VERSION 5.4 ;
NAMESCASESENSITIVE ON ;
BUSBITCHARS "[]" ;
DIVIDERCHAR "/" ;
UNITS
  DATABASE MICRONS 2000 ;
END UNITS
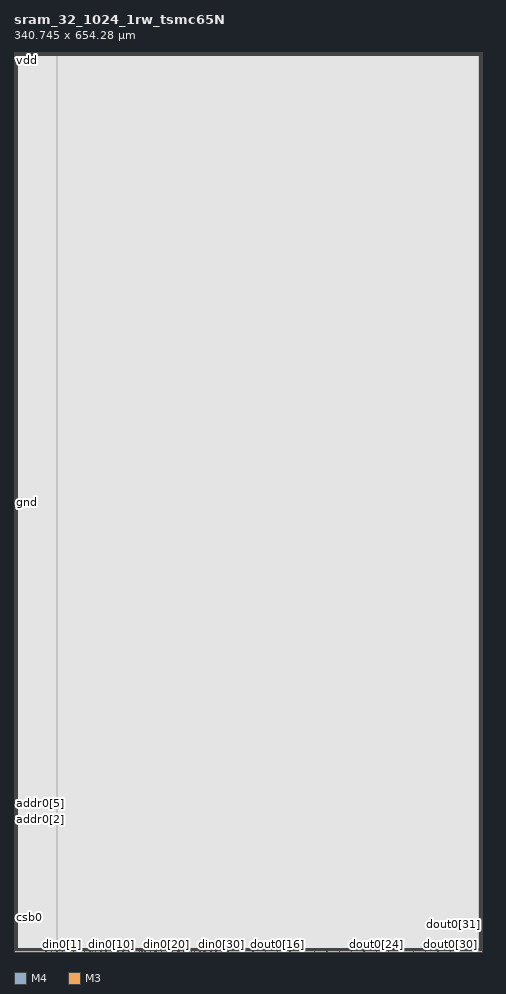
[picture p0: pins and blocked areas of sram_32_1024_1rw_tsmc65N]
MACRO sram_32_1024_1rw_tsmc65N
   CLASS BLOCK ;
   SIZE 340.745 BY 654.28 ;
   SYMMETRY X Y R90 ;
   PIN din0[0]
      DIRECTION INPUT ;
      PORT
         LAYER M4 ;
         RECT  31.095 0.0 31.315 0.22 ;
      END
   END din0[0]
   PIN din0[1]
      DIRECTION INPUT ;
      PORT
         LAYER M4 ;
         RECT  35.095 0.0 35.315 0.22 ;
      END
   END din0[1]
   PIN din0[2]
      DIRECTION INPUT ;
      PORT
         LAYER M4 ;
         RECT  39.095 0.0 39.315 0.22 ;
      END
   END din0[2]
   PIN din0[3]
      DIRECTION INPUT ;
      PORT
         LAYER M4 ;
         RECT  43.095 0.0 43.315 0.22 ;
      END
   END din0[3]
   PIN din0[4]
      DIRECTION INPUT ;
      PORT
         LAYER M4 ;
         RECT  47.095 0.0 47.315 0.22 ;
      END
   END din0[4]
   PIN din0[5]
      DIRECTION INPUT ;
      PORT
         LAYER M4 ;
         RECT  51.095 0.0 51.315 0.22 ;
      END
   END din0[5]
   PIN din0[6]
      DIRECTION INPUT ;
      PORT
         LAYER M4 ;
         RECT  55.095 0.0 55.315 0.22 ;
      END
   END din0[6]
   PIN din0[7]
      DIRECTION INPUT ;
      PORT
         LAYER M4 ;
         RECT  59.095 0.0 59.315 0.22 ;
      END
   END din0[7]
   PIN din0[8]
      DIRECTION INPUT ;
      PORT
         LAYER M4 ;
         RECT  63.095 0.0 63.315 0.22 ;
      END
   END din0[8]
   PIN din0[9]
      DIRECTION INPUT ;
      PORT
         LAYER M4 ;
         RECT  67.095 0.0 67.315 0.22 ;
      END
   END din0[9]
   PIN din0[10]
      DIRECTION INPUT ;
      PORT
         LAYER M4 ;
         RECT  71.095 0.0 71.315 0.22 ;
      END
   END din0[10]
   PIN din0[11]
      DIRECTION INPUT ;
      PORT
         LAYER M4 ;
         RECT  75.095 0.0 75.315 0.22 ;
      END
   END din0[11]
   PIN din0[12]
      DIRECTION INPUT ;
      PORT
         LAYER M4 ;
         RECT  79.095 0.0 79.315 0.22 ;
      END
   END din0[12]
   PIN din0[13]
      DIRECTION INPUT ;
      PORT
         LAYER M4 ;
         RECT  83.095 0.0 83.315 0.22 ;
      END
   END din0[13]
   PIN din0[14]
      DIRECTION INPUT ;
      PORT
         LAYER M4 ;
         RECT  87.095 0.0 87.315 0.22 ;
      END
   END din0[14]
   PIN din0[15]
      DIRECTION INPUT ;
      PORT
         LAYER M4 ;
         RECT  91.095 0.0 91.315 0.22 ;
      END
   END din0[15]
   PIN din0[16]
      DIRECTION INPUT ;
      PORT
         LAYER M4 ;
         RECT  95.095 0.0 95.315 0.22 ;
      END
   END din0[16]
   PIN din0[17]
      DIRECTION INPUT ;
      PORT
         LAYER M4 ;
         RECT  99.095 0.0 99.315 0.22 ;
      END
   END din0[17]
   PIN din0[18]
      DIRECTION INPUT ;
      PORT
         LAYER M4 ;
         RECT  103.095 0.0 103.315 0.22 ;
      END
   END din0[18]
   PIN din0[19]
      DIRECTION INPUT ;
      PORT
         LAYER M4 ;
         RECT  107.095 0.0 107.315 0.22 ;
      END
   END din0[19]
   PIN din0[20]
      DIRECTION INPUT ;
      PORT
         LAYER M4 ;
         RECT  111.095 0.0 111.315 0.22 ;
      END
   END din0[20]
   PIN din0[21]
      DIRECTION INPUT ;
      PORT
         LAYER M4 ;
         RECT  115.095 0.0 115.315 0.22 ;
      END
   END din0[21]
   PIN din0[22]
      DIRECTION INPUT ;
      PORT
         LAYER M4 ;
         RECT  119.095 0.0 119.315 0.22 ;
      END
   END din0[22]
   PIN din0[23]
      DIRECTION INPUT ;
      PORT
         LAYER M4 ;
         RECT  123.095 0.0 123.315 0.22 ;
      END
   END din0[23]
   PIN din0[24]
      DIRECTION INPUT ;
      PORT
         LAYER M4 ;
         RECT  127.095 0.0 127.315 0.22 ;
      END
   END din0[24]
   PIN din0[25]
      DIRECTION INPUT ;
      PORT
         LAYER M4 ;
         RECT  131.095 0.0 131.315 0.22 ;
      END
   END din0[25]
   PIN din0[26]
      DIRECTION INPUT ;
      PORT
         LAYER M4 ;
         RECT  135.095 0.0 135.315 0.22 ;
      END
   END din0[26]
   PIN din0[27]
      DIRECTION INPUT ;
      PORT
         LAYER M4 ;
         RECT  139.095 0.0 139.315 0.22 ;
      END
   END din0[27]
   PIN din0[28]
      DIRECTION INPUT ;
      PORT
         LAYER M4 ;
         RECT  143.095 0.0 143.315 0.22 ;
      END
   END din0[28]
   PIN din0[29]
      DIRECTION INPUT ;
      PORT
         LAYER M4 ;
         RECT  147.095 0.0 147.315 0.22 ;
      END
   END din0[29]
   PIN din0[30]
      DIRECTION INPUT ;
      PORT
         LAYER M4 ;
         RECT  151.095 0.0 151.315 0.22 ;
      END
   END din0[30]
   PIN din0[31]
      DIRECTION INPUT ;
      PORT
         LAYER M4 ;
         RECT  155.095 0.0 155.315 0.22 ;
      END
   END din0[31]
   PIN addr0[0]
      DIRECTION INPUT ;
      PORT
         LAYER M4 ;
         RECT  23.095 0.0 23.315 0.22 ;
      END
   END addr0[0]
   PIN addr0[1]
      DIRECTION INPUT ;
      PORT
         LAYER M4 ;
         RECT  27.095 0.0 27.315 0.22 ;
      END
   END addr0[1]
   PIN addr0[2]
      DIRECTION INPUT ;
      PORT
         LAYER M3 ;
         RECT  0.0 96.12 0.22 96.34 ;
      END
   END addr0[2]
   PIN addr0[3]
      DIRECTION INPUT ;
      PORT
         LAYER M3 ;
         RECT  0.0 98.45 0.22 98.67 ;
      END
   END addr0[3]
   PIN addr0[4]
      DIRECTION INPUT ;
      PORT
         LAYER M3 ;
         RECT  0.0 100.25 0.22 100.47 ;
      END
   END addr0[4]
   PIN addr0[5]
      DIRECTION INPUT ;
      PORT
         LAYER M3 ;
         RECT  0.0 102.05 0.22 102.27 ;
      END
   END addr0[5]
   PIN addr0[6]
      DIRECTION INPUT ;
      PORT
         LAYER M3 ;
         RECT  0.0 103.85 0.22 104.07 ;
      END
   END addr0[6]
   PIN addr0[7]
      DIRECTION INPUT ;
      PORT
         LAYER M3 ;
         RECT  0.0 105.65 0.22 105.87 ;
      END
   END addr0[7]
   PIN addr0[8]
      DIRECTION INPUT ;
      PORT
         LAYER M3 ;
         RECT  0.0 107.45 0.22 107.67 ;
      END
   END addr0[8]
   PIN addr0[9]
      DIRECTION INPUT ;
      PORT
         LAYER M3 ;
         RECT  0.0 109.25 0.22 109.47 ;
      END
   END addr0[9]
   PIN csb0
      DIRECTION INPUT ;
      PORT
         LAYER M3 ;
         RECT  0.0 24.8 0.22 25.02 ;
      END
   END csb0
   PIN web0
      DIRECTION INPUT ;
      PORT
         LAYER M3 ;
         RECT  0.0 26.6 0.22 26.82 ;
      END
   END web0
   PIN clk0
      DIRECTION INPUT ;
      PORT
         LAYER M3 ;
         RECT  0.0 24.45 0.22 24.67 ;
      END
   END clk0
   PIN dout0[0]
      DIRECTION OUTPUT ;
      PORT
         LAYER M4 ;
         RECT  48.25 0.0 48.47 0.22 ;
      END
   END dout0[0]
   PIN dout0[1]
      DIRECTION OUTPUT ;
      PORT
         LAYER M4 ;
         RECT  57.21 0.0 57.43 0.22 ;
      END
   END dout0[1]
   PIN dout0[2]
      DIRECTION OUTPUT ;
      PORT
         LAYER M4 ;
         RECT  66.17 0.0 66.39 0.22 ;
      END
   END dout0[2]
   PIN dout0[3]
      DIRECTION OUTPUT ;
      PORT
         LAYER M4 ;
         RECT  75.48 0.0 75.7 0.22 ;
      END
   END dout0[3]
   PIN dout0[4]
      DIRECTION OUTPUT ;
      PORT
         LAYER M4 ;
         RECT  84.09 0.0 84.31 0.22 ;
      END
   END dout0[4]
   PIN dout0[5]
      DIRECTION OUTPUT ;
      PORT
         LAYER M4 ;
         RECT  93.05 0.0 93.27 0.22 ;
      END
   END dout0[5]
   PIN dout0[6]
      DIRECTION OUTPUT ;
      PORT
         LAYER M4 ;
         RECT  102.01 0.0 102.23 0.22 ;
      END
   END dout0[6]
   PIN dout0[7]
      DIRECTION OUTPUT ;
      PORT
         LAYER M4 ;
         RECT  111.77 0.0 111.99 0.22 ;
      END
   END dout0[7]
   PIN dout0[8]
      DIRECTION OUTPUT ;
      PORT
         LAYER M4 ;
         RECT  119.93 0.0 120.15 0.22 ;
      END
   END dout0[8]
   PIN dout0[9]
      DIRECTION OUTPUT ;
      PORT
         LAYER M4 ;
         RECT  128.89 0.0 129.11 0.22 ;
      END
   END dout0[9]
   PIN dout0[10]
      DIRECTION OUTPUT ;
      PORT
         LAYER M4 ;
         RECT  137.95 0.0 138.17 0.22 ;
      END
   END dout0[10]
   PIN dout0[11]
      DIRECTION OUTPUT ;
      PORT
         LAYER M4 ;
         RECT  146.745 0.0 146.965 0.22 ;
      END
   END dout0[11]
   PIN dout0[12]
      DIRECTION OUTPUT ;
      PORT
         LAYER M4 ;
         RECT  155.77 0.0 155.99 0.22 ;
      END
   END dout0[12]
   PIN dout0[13]
      DIRECTION OUTPUT ;
      PORT
         LAYER M4 ;
         RECT  164.73 0.0 164.95 0.22 ;
      END
   END dout0[13]
   PIN dout0[14]
      DIRECTION OUTPUT ;
      PORT
         LAYER M4 ;
         RECT  173.69 0.0 173.91 0.22 ;
      END
   END dout0[14]
   PIN dout0[15]
      DIRECTION OUTPUT ;
      PORT
         LAYER M4 ;
         RECT  182.65 0.0 182.87 0.22 ;
      END
   END dout0[15]
   PIN dout0[16]
      DIRECTION OUTPUT ;
      PORT
         LAYER M4 ;
         RECT  191.61 0.0 191.83 0.22 ;
      END
   END dout0[16]
   PIN dout0[17]
      DIRECTION OUTPUT ;
      PORT
         LAYER M4 ;
         RECT  200.57 0.0 200.79 0.22 ;
      END
   END dout0[17]
   PIN dout0[18]
      DIRECTION OUTPUT ;
      PORT
         LAYER M4 ;
         RECT  209.53 0.0 209.75 0.22 ;
      END
   END dout0[18]
   PIN dout0[19]
      DIRECTION OUTPUT ;
      PORT
         LAYER M4 ;
         RECT  218.49 0.0 218.71 0.22 ;
      END
   END dout0[19]
   PIN dout0[20]
      DIRECTION OUTPUT ;
      PORT
         LAYER M4 ;
         RECT  227.45 0.0 227.67 0.22 ;
      END
   END dout0[20]
   PIN dout0[21]
      DIRECTION OUTPUT ;
      PORT
         LAYER M4 ;
         RECT  236.41 0.0 236.63 0.22 ;
      END
   END dout0[21]
   PIN dout0[22]
      DIRECTION OUTPUT ;
      PORT
         LAYER M4 ;
         RECT  245.37 0.0 245.59 0.22 ;
      END
   END dout0[22]
   PIN dout0[23]
      DIRECTION OUTPUT ;
      PORT
         LAYER M4 ;
         RECT  254.33 0.0 254.55 0.22 ;
      END
   END dout0[23]
   PIN dout0[24]
      DIRECTION OUTPUT ;
      PORT
         LAYER M4 ;
         RECT  263.29 0.0 263.51 0.22 ;
      END
   END dout0[24]
   PIN dout0[25]
      DIRECTION OUTPUT ;
      PORT
         LAYER M4 ;
         RECT  272.25 0.0 272.47 0.22 ;
      END
   END dout0[25]
   PIN dout0[26]
      DIRECTION OUTPUT ;
      PORT
         LAYER M4 ;
         RECT  281.21 0.0 281.43 0.22 ;
      END
   END dout0[26]
   PIN dout0[27]
      DIRECTION OUTPUT ;
      PORT
         LAYER M4 ;
         RECT  290.17 0.0 290.39 0.22 ;
      END
   END dout0[27]
   PIN dout0[28]
      DIRECTION OUTPUT ;
      PORT
         LAYER M4 ;
         RECT  299.13 0.0 299.35 0.22 ;
      END
   END dout0[28]
   PIN dout0[29]
      DIRECTION OUTPUT ;
      PORT
         LAYER M4 ;
         RECT  308.09 0.0 308.31 0.22 ;
      END
   END dout0[29]
   PIN dout0[30]
      DIRECTION OUTPUT ;
      PORT
         LAYER M4 ;
         RECT  317.05 0.0 317.27 0.22 ;
      END
   END dout0[30]
   PIN dout0[31]
      DIRECTION OUTPUT ;
      PORT
         LAYER M3 ;
         RECT  340.525 20.055 340.745 20.275 ;
      END
   END dout0[31]
   PIN vdd
      DIRECTION INOUT ;
      USE POWER ; 
      SHAPE ABUTMENT ; 
      PORT
         LAYER M4 ;
         RECT  339.845 0.0 340.745 654.28 ;
         LAYER M3 ;
         RECT  0.0 653.38 340.745 654.28 ;
         LAYER M4 ;
         RECT  0.0 0.0 0.9 654.28 ;
         LAYER M3 ;
         RECT  0.0 0.0 340.745 0.9 ;
      END
   END vdd
   PIN gnd
      DIRECTION INOUT ;
      USE GROUND ; 
      SHAPE ABUTMENT ; 
      PORT
         LAYER M4 ;
         RECT  338.045 1.8 338.945 652.48 ;
         LAYER M3 ;
         RECT  1.8 1.8 338.945 2.7 ;
         LAYER M3 ;
         RECT  1.8 651.58 338.945 652.48 ;
         LAYER M4 ;
         RECT  1.8 1.8 2.7 652.48 ;
      END
   END gnd
   OBS
   LAYER  M1 ;
      RECT  0.32 0.32 340.425 653.96 ;
   LAYER  M2 ;
      RECT  0.32 0.32 340.425 653.96 ;
   LAYER  M3 ;
      RECT  0.42 95.92 340.425 96.54 ;
      RECT  0.32 96.54 0.42 98.25 ;
      RECT  0.32 98.87 0.42 100.05 ;
      RECT  0.32 100.67 0.42 101.85 ;
      RECT  0.32 102.47 0.42 103.65 ;
      RECT  0.32 104.27 0.42 105.45 ;
      RECT  0.32 106.07 0.42 107.25 ;
      RECT  0.32 107.87 0.42 109.05 ;
      RECT  0.32 25.22 0.42 26.4 ;
      RECT  0.32 27.02 0.42 95.92 ;
      RECT  0.42 19.855 340.325 20.475 ;
      RECT  0.42 20.475 340.325 95.92 ;
      RECT  340.325 20.475 340.425 95.92 ;
      RECT  0.32 109.67 0.42 653.18 ;
      RECT  0.32 1.1 0.42 24.25 ;
      RECT  340.325 1.1 340.425 19.855 ;
      RECT  0.42 1.1 1.6 1.6 ;
      RECT  0.42 1.6 1.6 2.9 ;
      RECT  0.42 2.9 1.6 19.855 ;
      RECT  1.6 1.1 339.145 1.6 ;
      RECT  1.6 2.9 339.145 19.855 ;
      RECT  339.145 1.1 340.325 1.6 ;
      RECT  339.145 1.6 340.325 2.9 ;
      RECT  339.145 2.9 340.325 19.855 ;
      RECT  0.42 96.54 1.6 651.38 ;
      RECT  0.42 651.38 1.6 652.68 ;
      RECT  0.42 652.68 1.6 653.18 ;
      RECT  1.6 96.54 339.145 651.38 ;
      RECT  1.6 652.68 339.145 653.18 ;
      RECT  339.145 96.54 340.425 651.38 ;
      RECT  339.145 651.38 340.425 652.68 ;
      RECT  339.145 652.68 340.425 653.18 ;
   LAYER  M4 ;
      RECT  30.895 0.42 31.515 653.96 ;
      RECT  31.515 0.32 34.895 0.42 ;
      RECT  35.515 0.32 38.895 0.42 ;
      RECT  39.515 0.32 42.895 0.42 ;
      RECT  43.515 0.32 46.895 0.42 ;
      RECT  51.515 0.32 54.895 0.42 ;
      RECT  59.515 0.32 62.895 0.42 ;
      RECT  67.515 0.32 70.895 0.42 ;
      RECT  71.515 0.32 74.895 0.42 ;
      RECT  79.515 0.32 82.895 0.42 ;
      RECT  87.515 0.32 90.895 0.42 ;
      RECT  95.515 0.32 98.895 0.42 ;
      RECT  103.515 0.32 106.895 0.42 ;
      RECT  107.515 0.32 110.895 0.42 ;
      RECT  115.515 0.32 118.895 0.42 ;
      RECT  123.515 0.32 126.895 0.42 ;
      RECT  131.515 0.32 134.895 0.42 ;
      RECT  139.515 0.32 142.895 0.42 ;
      RECT  147.515 0.32 150.895 0.42 ;
      RECT  151.515 0.32 154.895 0.42 ;
      RECT  23.515 0.32 26.895 0.42 ;
      RECT  27.515 0.32 30.895 0.42 ;
      RECT  47.515 0.32 48.05 0.42 ;
      RECT  48.67 0.32 50.895 0.42 ;
      RECT  55.515 0.32 57.01 0.42 ;
      RECT  57.63 0.32 58.895 0.42 ;
      RECT  63.515 0.32 65.97 0.42 ;
      RECT  66.59 0.32 66.895 0.42 ;
      RECT  75.9 0.32 78.895 0.42 ;
      RECT  83.515 0.32 83.89 0.42 ;
      RECT  84.51 0.32 86.895 0.42 ;
      RECT  91.515 0.32 92.85 0.42 ;
      RECT  93.47 0.32 94.895 0.42 ;
      RECT  99.515 0.32 101.81 0.42 ;
      RECT  102.43 0.32 102.895 0.42 ;
      RECT  111.515 0.32 111.57 0.42 ;
      RECT  112.19 0.32 114.895 0.42 ;
      RECT  119.515 0.32 119.73 0.42 ;
      RECT  120.35 0.32 122.895 0.42 ;
      RECT  127.515 0.32 128.69 0.42 ;
      RECT  129.31 0.32 130.895 0.42 ;
      RECT  135.515 0.32 137.75 0.42 ;
      RECT  138.37 0.32 138.895 0.42 ;
      RECT  143.515 0.32 146.545 0.42 ;
      RECT  155.515 0.32 155.57 0.42 ;
      RECT  156.19 0.32 164.53 0.42 ;
      RECT  165.15 0.32 173.49 0.42 ;
      RECT  174.11 0.32 182.45 0.42 ;
      RECT  183.07 0.32 191.41 0.42 ;
      RECT  192.03 0.32 200.37 0.42 ;
      RECT  200.99 0.32 209.33 0.42 ;
      RECT  209.95 0.32 218.29 0.42 ;
      RECT  218.91 0.32 227.25 0.42 ;
      RECT  227.87 0.32 236.21 0.42 ;
      RECT  236.83 0.32 245.17 0.42 ;
      RECT  245.79 0.32 254.13 0.42 ;
      RECT  254.75 0.32 263.09 0.42 ;
      RECT  263.71 0.32 272.05 0.42 ;
      RECT  272.67 0.32 281.01 0.42 ;
      RECT  281.63 0.32 289.97 0.42 ;
      RECT  290.59 0.32 298.93 0.42 ;
      RECT  299.55 0.32 307.89 0.42 ;
      RECT  308.51 0.32 316.85 0.42 ;
      RECT  317.47 0.32 339.645 0.42 ;
      RECT  1.1 0.32 22.895 0.42 ;
      RECT  31.515 0.42 337.845 1.6 ;
      RECT  31.515 1.6 337.845 652.68 ;
      RECT  31.515 652.68 337.845 653.96 ;
      RECT  337.845 0.42 339.145 1.6 ;
      RECT  337.845 652.68 339.145 653.96 ;
      RECT  339.145 0.42 339.645 1.6 ;
      RECT  339.145 1.6 339.645 652.68 ;
      RECT  339.145 652.68 339.645 653.96 ;
      RECT  1.1 0.42 1.6 1.6 ;
      RECT  1.1 1.6 1.6 652.68 ;
      RECT  1.1 652.68 1.6 653.96 ;
      RECT  1.6 0.42 2.9 1.6 ;
      RECT  1.6 652.68 2.9 653.96 ;
      RECT  2.9 0.42 30.895 1.6 ;
      RECT  2.9 1.6 30.895 652.68 ;
      RECT  2.9 652.68 30.895 653.96 ;
   END
END    sram_32_1024_1rw_tsmc65N
END    LIBRARY
